One B-rep face of a CAD part: STEP entity #799.
In plain terms, the planar face has unit normal (0, 0, -1).
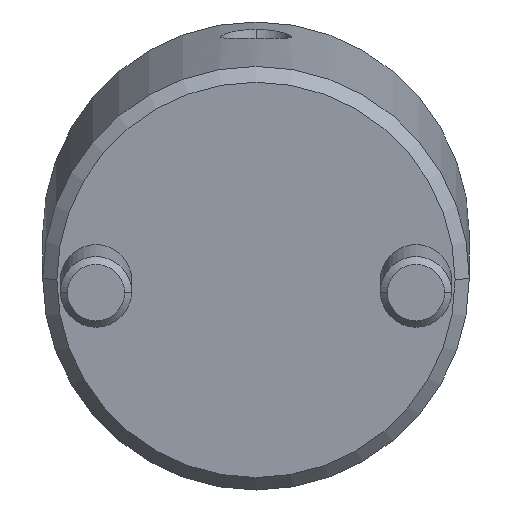
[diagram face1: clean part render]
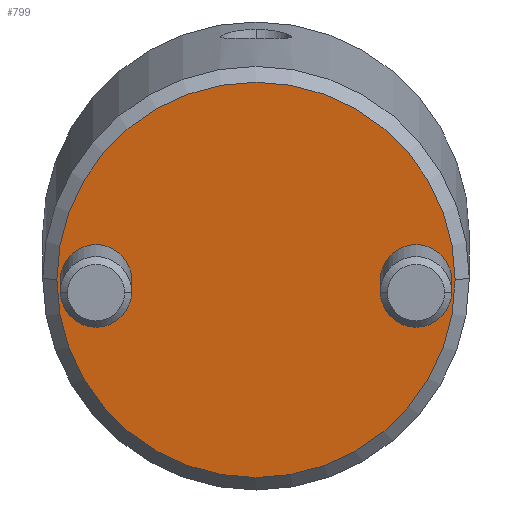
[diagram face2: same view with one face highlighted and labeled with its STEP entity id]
Its self-contained STEP definition (entity closure, numbers rounded to 3 decimals):
#420=CARTESIAN_POINT('',(0.,0.,0.));
#421=DIRECTION('',(0.,0.,-1.));
#422=DIRECTION('',(0.,-1.,0.));
#423=AXIS2_PLACEMENT_3D('',#420,#421,#422);
#425=CARTESIAN_POINT('',(0.,0.,
0.));
#426=DIRECTION('',(0.,0.,-1.));
#427=DIRECTION('',(0.,1.,0.));
#428=AXIS2_PLACEMENT_3D('',#425,#426,#427);
#430=CARTESIAN_POINT('',(0.,-11.25,0.));
#431=DIRECTION('',(0.,0.,-1.));
#432=DIRECTION('',(0.,-1.,0.));
#433=AXIS2_PLACEMENT_3D('',#430,#431,#432);
#435=CARTESIAN_POINT('',(0.,-11.25,0.));
#436=DIRECTION('',(0.,0.,-1.));
#437=DIRECTION('',(0.,1.,0.));
#438=AXIS2_PLACEMENT_3D('',#435,#436,#437);
#440=CARTESIAN_POINT('',(0.,11.25,0.));
#441=DIRECTION('',(0.,0.,-1.));
#442=DIRECTION('',(0.,-1.,0.));
#443=AXIS2_PLACEMENT_3D('',#440,#441,#442);
#445=CARTESIAN_POINT('',(0.,11.25,0.));
#446=DIRECTION('',(0.,0.,-1.));
#447=DIRECTION('',(0.,1.,0.));
#448=AXIS2_PLACEMENT_3D('',#445,#446,#447);
#726=CARTESIAN_POINT('',(0.,-14.,0.));
#727=CARTESIAN_POINT('',(0.,14.,0.));
#728=VERTEX_POINT('',#726);
#729=VERTEX_POINT('',#727);
#752=CARTESIAN_POINT('',(0.,-13.75,0.));
#753=CARTESIAN_POINT('',(0.,-8.75,0.));
#754=VERTEX_POINT('',#752);
#755=VERTEX_POINT('',#753);
#756=CARTESIAN_POINT('',(0.,8.75,0.));
#757=CARTESIAN_POINT('',(0.,13.75,0.));
#758=VERTEX_POINT('',#756);
#759=VERTEX_POINT('',#757);
#776=CARTESIAN_POINT('',(0.,0.,0.));
#777=DIRECTION('',(0.,0.,1.));
#778=DIRECTION('',(0.,1.,0.));
#779=AXIS2_PLACEMENT_3D('',#776,#777,#778);
#780=PLANE('',#779);
#782=ORIENTED_EDGE('',*,*,#781,.F.);
#784=ORIENTED_EDGE('',*,*,#783,.F.);
#785=EDGE_LOOP('',(#782,#784));
#786=FACE_OUTER_BOUND('',#785,.F.);
#788=ORIENTED_EDGE('',*,*,#787,.T.);
#790=ORIENTED_EDGE('',*,*,#789,.T.);
#791=EDGE_LOOP('',(#788,#790));
#792=FACE_BOUND('',#791,.F.);
#794=ORIENTED_EDGE('',*,*,#793,.T.);
#796=ORIENTED_EDGE('',*,*,#795,.T.);
#797=EDGE_LOOP('',(#794,#796));
#798=FACE_BOUND('',#797,.F.);
#799=ADVANCED_FACE('',(#786,#792,#798),#780,.F.);
#424=CIRCLE('',#423,14.);
#429=CIRCLE('',#428,14.);
#434=CIRCLE('',#433,2.5);
#439=CIRCLE('',#438,2.5);
#444=CIRCLE('',#443,2.5);
#449=CIRCLE('',#448,2.5);
#781=EDGE_CURVE('',#728,#729,#424,.T.);
#783=EDGE_CURVE('',#729,#728,#429,.T.);
#787=EDGE_CURVE('',#754,#755,#434,.T.);
#789=EDGE_CURVE('',#755,#754,#439,.T.);
#793=EDGE_CURVE('',#758,#759,#444,.T.);
#795=EDGE_CURVE('',#759,#758,#449,.T.);
